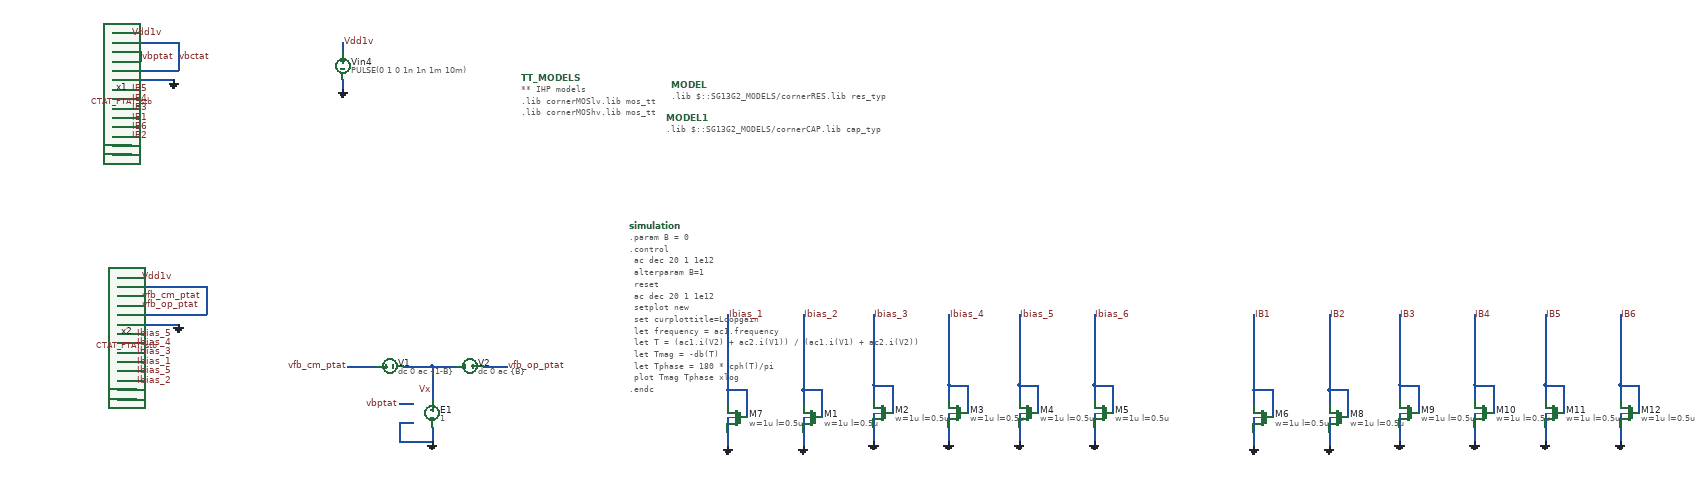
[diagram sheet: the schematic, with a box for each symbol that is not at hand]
v {xschem version=3.4.6 file_version=1.2}
G {}
K {}
V {}
S {}
E {}
P 4 1 2030 -650 {}
N 1560 -1170 1560 -1150 {lab=GND}
N 1560 -1250 1560 -1230 {lab=Vdd1v}
N 1070 -1270 1110 -1270 {lab=Vdd1v}
N 1070 -1250 1210 -1250 {lab=vbctat}
N 1210 -1250 1210 -1190 {lab=vbctat}
N 1070 -1190 1210 -1190 {lab=vbctat}
N 1070 -1210 1130 -1210 {lab=vbptat}
N 1130 -1230 1130 -1210 {lab=vbptat}
N 1070 -1230 1130 -1230 {lab=vbptat}
N 1070 -1170 1200 -1170 {lab=GND}
N 1070 -1090 1110 -1090 {lab=IB1}
N 1070 -1110 1110 -1110 {lab=IB3}
N 1070 -1130 1110 -1130 {lab=IB4}
N 1070 -1150 1110 -1150 {lab=IB5}
N 1070 -1070 1110 -1070 {lab=IB6}
N 1070 -1050 1110 -1050 {lab=IB2}
N 1070 -1030 1110 -1030 {lab=#net1}
N 1070 -1010 1110 -1010 {lab=#net2}
N 1080 -650 1210 -650 {lab=GND}
N 1080 -570 1120 -570 {lab=Ibias_1}
N 1080 -590 1120 -590 {lab=Ibias_3}
N 1080 -610 1120 -610 {lab=Ibias_4}
N 1080 -630 1120 -630 {lab=Ibias_5}
N 1080 -550 1120 -550 {lab=Ibias_5}
N 1080 -530 1120 -530 {lab=Ibias_2}
N 1080 -510 1120 -510 {lab=#net3}
N 1080 -490 1120 -490 {lab=#net4}
N 1080 -750 1130 -750 {lab=Vdd1v}
N 1080 -730 1270 -730 {lab=#net5}
N 1080 -710 1130 -710 {lab=vfb_cm_ptat}
N 1080 -690 1130 -690 {lab=vfb_op_ptat}
N 1080 -670 1270 -670 {lab=#net5}
N 1750 -560 1800 -560 {lab=Vx}
N 1570 -560 1630 -560 {lab=vfb_cm_ptat}
N 1690 -560 1750 -560 {lab=Vx}
N 1680 -440 1710 -440 {lab=GND}
N 1680 -440 1680 -400 {lab=GND}
N 1680 -400 1750 -400 {lab=GND}
N 1750 -430 1750 -400 {lab=GND}
N 1750 -560 1750 -490 {lab=Vx}
N 1680 -480 1710 -480 {lab=vbptat}
N 2380 -510 2380 -480 {lab=Ibias_1}
N 2420 -510 2420 -450 {lab=Ibias_1}
N 2380 -510 2420 -510 {lab=Ibias_1}
N 2380 -450 2380 -390 {lab=GND}
N 2540 -510 2540 -480 {lab=Ibias_2}
N 2580 -510 2580 -450 {lab=Ibias_2}
N 2540 -510 2580 -510 {lab=Ibias_2}
N 2540 -450 2540 -390 {lab=GND}
N 2690 -520 2690 -490 {lab=Ibias_3}
N 2730 -520 2730 -460 {lab=Ibias_3}
N 2690 -520 2730 -520 {lab=Ibias_3}
N 2690 -460 2690 -400 {lab=GND}
N 2850 -520 2850 -490 {lab=Ibias_4}
N 2890 -520 2890 -460 {lab=Ibias_4}
N 2850 -520 2890 -520 {lab=Ibias_4}
N 2850 -460 2850 -400 {lab=GND}
N 3000 -520 3000 -490 {lab=Ibias_5}
N 3040 -520 3040 -460 {lab=Ibias_5}
N 3000 -520 3040 -520 {lab=Ibias_5}
N 3000 -460 3000 -400 {lab=GND}
N 3160 -520 3160 -490 {lab=Ibias_6}
N 3200 -520 3200 -460 {lab=Ibias_6}
N 3160 -520 3200 -520 {lab=Ibias_6}
N 3160 -460 3160 -400 {lab=GND}
N 2380 -670 2380 -510 {lab=Ibias_1}
N 2540 -670 2540 -510 {lab=Ibias_2}
N 2690 -670 2690 -520 {lab=Ibias_3}
N 2850 -670 2850 -520 {lab=Ibias_4}
N 3000 -670 3000 -520 {lab=Ibias_5}
N 3160 -670 3160 -520 {lab=Ibias_6}
N 3500 -510 3500 -480 {lab=IB1}
N 3540 -510 3540 -450 {lab=IB1}
N 3500 -510 3540 -510 {lab=IB1}
N 3500 -450 3500 -390 {lab=GND}
N 3660 -510 3660 -480 {lab=IB2}
N 3700 -510 3700 -450 {lab=IB2}
N 3660 -510 3700 -510 {lab=IB2}
N 3660 -450 3660 -390 {lab=GND}
N 3810 -520 3810 -490 {lab=IB3}
N 3850 -520 3850 -460 {lab=IB3}
N 3810 -520 3850 -520 {lab=IB3}
N 3810 -460 3810 -400 {lab=GND}
N 3970 -520 3970 -490 {lab=IB4}
N 4010 -520 4010 -460 {lab=IB4}
N 3970 -520 4010 -520 {lab=IB4}
N 3970 -460 3970 -400 {lab=GND}
N 4120 -520 4120 -490 {lab=IB5}
N 4160 -520 4160 -460 {lab=IB5}
N 4120 -520 4160 -520 {lab=IB5}
N 4120 -460 4120 -400 {lab=GND}
N 4280 -520 4280 -490 {lab=IB6}
N 4320 -520 4320 -460 {lab=IB6}
N 4280 -520 4320 -520 {lab=IB6}
N 4280 -460 4280 -400 {lab=GND}
N 3500 -670 3500 -510 {lab=IB1}
N 3660 -670 3660 -510 {lab=IB2}
N 3810 -670 3810 -520 {lab=IB3}
N 3970 -670 3970 -520 {lab=IB4}
N 4120 -670 4120 -520 {lab=IB5}
N 4280 -670 4280 -520 {lab=IB6}
N 1860 -560 1910 -560 {lab=vfb_op_ptat}
N 1270 -730 1270 -670 {lab=#net5}
C {/shared/designs/SSDOR_1.2V_v2/components/Ib_4u/CTAT_PTAT/CTAT_PTAT_stb.sym} 920 -1140 0 0 {name=x1}
C {/shared/designs/SSDOR_1.2V_v2/components/Ib_4u/CTAT_PTAT/CTAT_PTAT_stb.sym} 930 -620 0 0 {name=x2}
C {gnd.sym} 1560 -1150 0 0 {name=l13 lab=GND}
C {vsource.sym} 1560 -1200 0 1 {name=Vin4 value="PULSE(0 1 0 1n 1n 1m 10m)" savecurrent=false}
C {lab_pin.sym} 1560 -1250 0 1 {name=p5 sig_type=std_logic lab=Vdd1v}
C {lab_pin.sym} 1110 -1270 0 1 {name=p1 sig_type=std_logic lab=Vdd1v}
C {gnd.sym} 1200 -1170 0 0 {name=l1 lab=GND}
C {gnd.sym} 1210 -650 0 0 {name=l2 lab=GND}
C {lab_pin.sym} 1130 -750 0 1 {name=p19 sig_type=std_logic lab=Vdd1v}
C {lab_pin.sym} 1570 -560 0 0 {name=p21 sig_type=std_logic lab=vfb_cm_ptat}
C {lab_pin.sym} 1910 -560 0 1 {name=p23 sig_type=std_logic lab=vfb_op_ptat}
C {lab_pin.sym} 1130 -1220 0 1 {name=p24 sig_type=std_logic lab=vbptat}
C {lab_pin.sym} 1210 -1220 0 1 {name=p25 sig_type=std_logic lab=vbctat}
C {vsource.sym} 1660 -560 3 0 {name=V1 value="dc 0 ac \{1-B\}" savecurrent=false}
C {vcvs.sym} 1750 -460 0 0 {name=E1 value="1"}
C {lab_pin.sym} 1680 -480 0 0 {name=p28 sig_type=std_logic lab=vbptat}
C {gnd.sym} 1750 -400 0 0 {name=l3 lab=GND}
C {lab_pin.sym} 1750 -510 0 0 {name=p29 sig_type=std_logic lab=Vx}
C {code_shown.sym} 1940 -1175 0 0 {
name=TT_MODELS
only_toplevel=true
value="
** IHP models
.lib cornerMOSlv.lib mos_tt
.lib cornerMOShv.lib mos_tt
"
spice_ignore=false
      }
C {devices/code_shown.sym} 2260 -1160 0 0 {name=MODEL only_toplevel=true
format="tcleval( @value )"
value="
.lib $::SG13G2_MODELS/cornerRES.lib res_typ
"}
C {devices/code_shown.sym} 2250 -1090 0 0 {name=MODEL1 only_toplevel=true
format="tcleval( @value )"
value="
.lib $::SG13G2_MODELS/cornerCAP.lib cap_typ
"}
C {code.sym} 2170 -860 0 1 {name=simulation only_toplevel=false 
value="

.param B = 0
.control
 ac dec 20 1 1e12
 alterparam B=1
 reset
 ac dec 20 1 1e12
 setplot new
 set curplottitle=Loopgain
 let frequency = ac1.frequency
 let T = (ac1.i(V2) + ac2.i(V1)) / (ac1.i(V1) + ac2.i(V2))
 let Tmag = -db(T)
 let Tphase = 180 * cph(T)/pi
 plot Tmag Tphase xlog
.endc

"}
C {vsource.sym} 1830 -560 1 1 {name=V2 value="dc 0 ac \{B\}" savecurrent=false}
C {sg13g2_pr/sg13_lv_nmos.sym} 2400 -450 0 1 {name=M7
l=0.5u
w=1u
ng=1
m=1
model=sg13_lv_nmos
spiceprefix=X
}
C {gnd.sym} 2380 -390 0 0 {name=l4 lab=GND}
C {sg13g2_pr/sg13_lv_nmos.sym} 2560 -450 0 1 {name=M1
l=0.5u
w=1u
ng=1
m=1
model=sg13_lv_nmos
spiceprefix=X
}
C {gnd.sym} 2540 -390 0 0 {name=l5 lab=GND}
C {sg13g2_pr/sg13_lv_nmos.sym} 2710 -460 0 1 {name=M2
l=0.5u
w=1u
ng=1
m=1
model=sg13_lv_nmos
spiceprefix=X
}
C {gnd.sym} 2690 -400 0 0 {name=l6 lab=GND}
C {sg13g2_pr/sg13_lv_nmos.sym} 2870 -460 0 1 {name=M3
l=0.5u
w=1u
ng=1
m=1
model=sg13_lv_nmos
spiceprefix=X
}
C {gnd.sym} 2850 -400 0 0 {name=l7 lab=GND}
C {sg13g2_pr/sg13_lv_nmos.sym} 3020 -460 0 1 {name=M4
l=0.5u
w=1u
ng=1
m=1
model=sg13_lv_nmos
spiceprefix=X
}
C {gnd.sym} 3000 -400 0 0 {name=l8 lab=GND}
C {sg13g2_pr/sg13_lv_nmos.sym} 3180 -460 0 1 {name=M5
l=0.5u
w=1u
ng=1
m=1
model=sg13_lv_nmos
spiceprefix=X
}
C {gnd.sym} 3160 -400 0 0 {name=l9 lab=GND}
C {lab_pin.sym} 2380 -670 0 1 {name=p11 sig_type=std_logic lab=Ibias_1}
C {lab_pin.sym} 2540 -670 0 1 {name=p12 sig_type=std_logic lab=Ibias_2}
C {lab_pin.sym} 2690 -670 0 1 {name=p13 sig_type=std_logic lab=Ibias_3}
C {lab_pin.sym} 2850 -670 0 1 {name=p14 sig_type=std_logic lab=Ibias_4}
C {lab_pin.sym} 3000 -670 0 1 {name=p15 sig_type=std_logic lab=Ibias_5}
C {lab_pin.sym} 3160 -670 0 1 {name=p16 sig_type=std_logic lab=Ibias_6}
C {lab_pin.sym} 1120 -570 0 1 {name=p17 sig_type=std_logic lab=Ibias_1}
C {lab_pin.sym} 1120 -530 0 1 {name=p18 sig_type=std_logic lab=Ibias_2}
C {lab_pin.sym} 1120 -590 0 1 {name=p20 sig_type=std_logic lab=Ibias_3}
C {lab_pin.sym} 1120 -610 0 1 {name=p22 sig_type=std_logic lab=Ibias_4}
C {lab_pin.sym} 1120 -630 0 1 {name=p30 sig_type=std_logic lab=Ibias_5}
C {lab_pin.sym} 1120 -550 0 1 {name=p31 sig_type=std_logic lab=Ibias_5}
C {sg13g2_pr/sg13_lv_nmos.sym} 3520 -450 0 1 {name=M6
l=0.5u
w=1u
ng=1
m=1
model=sg13_lv_nmos
spiceprefix=X
}
C {gnd.sym} 3500 -390 0 0 {name=l10 lab=GND}
C {sg13g2_pr/sg13_lv_nmos.sym} 3680 -450 0 1 {name=M8
l=0.5u
w=1u
ng=1
m=1
model=sg13_lv_nmos
spiceprefix=X
}
C {gnd.sym} 3660 -390 0 0 {name=l11 lab=GND}
C {sg13g2_pr/sg13_lv_nmos.sym} 3830 -460 0 1 {name=M9
l=0.5u
w=1u
ng=1
m=1
model=sg13_lv_nmos
spiceprefix=X
}
C {gnd.sym} 3810 -400 0 0 {name=l12 lab=GND}
C {sg13g2_pr/sg13_lv_nmos.sym} 3990 -460 0 1 {name=M10
l=0.5u
w=1u
ng=1
m=1
model=sg13_lv_nmos
spiceprefix=X
}
C {gnd.sym} 3970 -400 0 0 {name=l14 lab=GND}
C {sg13g2_pr/sg13_lv_nmos.sym} 4140 -460 0 1 {name=M11
l=0.5u
w=1u
ng=1
m=1
model=sg13_lv_nmos
spiceprefix=X
}
C {gnd.sym} 4120 -400 0 0 {name=l15 lab=GND}
C {sg13g2_pr/sg13_lv_nmos.sym} 4300 -460 0 1 {name=M12
l=0.5u
w=1u
ng=1
m=1
model=sg13_lv_nmos
spiceprefix=X
}
C {gnd.sym} 4280 -400 0 0 {name=l16 lab=GND}
C {lab_pin.sym} 3500 -670 0 1 {name=p32 sig_type=std_logic lab=IB1}
C {lab_pin.sym} 3660 -670 0 1 {name=p33 sig_type=std_logic lab=IB2}
C {lab_pin.sym} 3810 -670 0 1 {name=p34 sig_type=std_logic lab=IB3}
C {lab_pin.sym} 3970 -670 0 1 {name=p35 sig_type=std_logic lab=IB4}
C {lab_pin.sym} 4120 -670 0 1 {name=p36 sig_type=std_logic lab=IB5}
C {lab_pin.sym} 4280 -670 0 1 {name=p37 sig_type=std_logic lab=IB6}
C {lab_pin.sym} 1110 -1090 0 1 {name=p38 sig_type=std_logic lab=IB1}
C {lab_pin.sym} 1110 -1050 0 1 {name=p39 sig_type=std_logic lab=IB2}
C {lab_pin.sym} 1110 -1110 0 1 {name=p40 sig_type=std_logic lab=IB3}
C {lab_pin.sym} 1110 -1130 0 1 {name=p41 sig_type=std_logic lab=IB4}
C {lab_pin.sym} 1110 -1150 0 1 {name=p42 sig_type=std_logic lab=IB5}
C {lab_pin.sym} 1110 -1070 0 1 {name=p43 sig_type=std_logic lab=IB6}
C {lab_pin.sym} 1130 -710 0 1 {name=p2 sig_type=std_logic lab=vfb_cm_ptat}
C {lab_pin.sym} 1130 -690 0 1 {name=p3 sig_type=std_logic lab=vfb_op_ptat}
